# RL6678_IP_SVD register map
Vendor: Realtek
Registers are 32-bit, read-write, reset 0x0 unless marked. A register's access mark holds for its fields unless they carry their own. Offsets are from the block's base; [hi:lo] are bit positions; {n}, {i} and the like mark numbered series.

## TXPWR_CTRL
Base 0x40000000
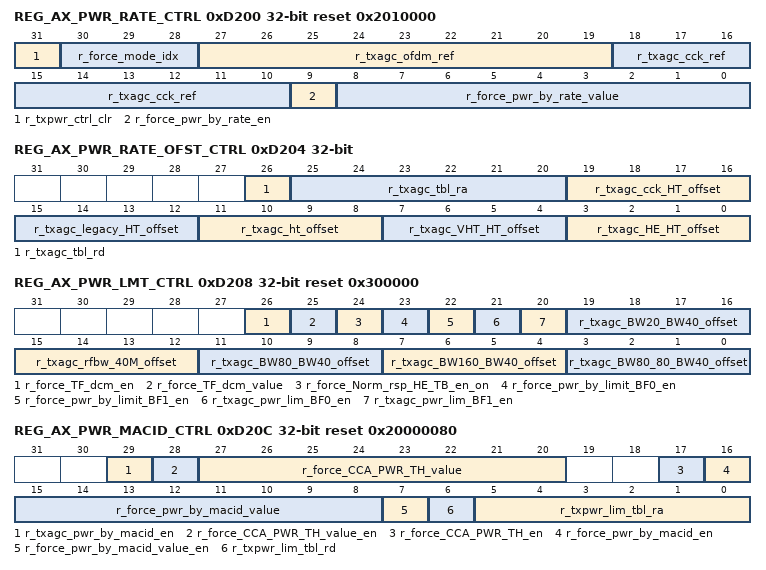
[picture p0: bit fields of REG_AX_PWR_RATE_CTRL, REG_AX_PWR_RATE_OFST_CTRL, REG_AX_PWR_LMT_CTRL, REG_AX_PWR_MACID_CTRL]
0xD200 REG_AX_PWR_RATE_CTRL reset 0x2010000
  [31] r_txpwr_ctrl_clr — (RTL_only) 1: clr txpwr, sync rst
  [30:28] r_force_mode_idx — Force txpwr_bb from specific source 0:FOCRE_NONE (normal) 1:FORCE_PWR_BY_RATE 2:FORCE_MACID 3:FORCE_PWR_LIM 4:FORCE_PWR_RU_LIM 5:FORCE_COEXIST
  [27:19] r_txagc_ofdm_ref — S(9.2) ofdm ref dbm
  [18:10] r_txagc_cck_ref — S(9.2) cck ref dbm
  [9] r_force_pwr_by_rate_en — force pwr by rate value_en
  [8:0] r_force_pwr_by_rate_value — S(9.2) force pwr by rate value (txagc_ref+pwr_by_rate_tbl)
0xD204 REG_AX_PWR_RATE_OFST_CTRL
  [26] r_txagc_tbl_rd — (RTL_only) 1:indirecr read enable
  [25:20] r_txagc_tbl_ra — (RTL_only) indirect read of addr of pwr_by_rate
  [19:16] r_txagc_cck_HT_offset — S(4.1)CCK-HT pwr offset
  [15:12] r_txagc_legacy_HT_offset — S(4.1)LEG-HT pwr offset
  [11:8] r_txagc_ht_offset — (RTL_only) S(4.1) HT-HT pwr bias = 0
  [7:4] r_txagc_VHT_HT_offset — S(4.1)VHT-HT pwr offset
  [3:0] r_txagc_HE_HT_offset — S(4.1)HE-HT pwr offset
0xD208 REG_AX_PWR_LMT_CTRL reset 0x300000
  [26] r_force_TF_dcm_en — (RTL_only) 1:Force input TF dcm = R_force_TF_dcm_value
  [25] r_force_TF_dcm_value — (RTL_only) Force input TF dcm value
  [24] r_force_Norm_rsp_HE_TB_en_on — (RTL_only) 1:Norm resp always In HE_TB
  [23] r_force_pwr_by_limit_BF0_en — (RTL_only) 1: Force pwr_lim_BF0= r_force_pwr_by_limit_bfoff_value (0xd210[17:9])
  [22] r_force_pwr_by_limit_BF1_en — (RTL_only) 1: Force pwr_lim_BF1= r_force_pwr_by_limit_bfon_value (0xd210[8:0])
  [21] r_txagc_pwr_lim_BF0_en — (RTL_only) None BF pwr limit enable
  [20] r_txagc_pwr_lim_BF1_en — (RTL_only) BF pwr limit enable
  [19:16] r_txagc_BW20_BW40_offset — S(4.1)BW20 - BW40 pwr offset
  [15:12] r_txagc_rfbw_40M_offset — (RTL_only) S(4.1)BW40 - BW40 pwr offset
  [11:8] r_txagc_BW80_BW40_offset — S(4.1)BW80 - BW40 pwr offset
  [7:4] r_txagc_BW160_BW40_offset — S(4.1)BW160 - BW40 pwr offset
  [3:0] r_txagc_BW80_80_BW40_offset — S(4.1) BW80+80 - BW40 pwr offset
0xD20C REG_AX_PWR_MACID_CTRL reset 0x20000080
  [29] r_txagc_pwr_by_macid_en — (RTL_only) 1:enable pwr_by_macid
  [28] r_force_CCA_PWR_TH_value_en — 1:Force CCA_PWR_TH value_en
  [27:20] r_force_CCA_PWR_TH_value — S(8.1)Force CCA_PWR_TH value
  [17] r_force_CCA_PWR_TH_en — (RTL_only) 1:Force output CCA_PWR_TH_en
  [16] r_force_pwr_by_macid_en — 1:Force output Pwr_by_macid_en
  [15:8] r_force_pwr_by_macid_value — S(8.1)Force Pwr_by_macid_value
  [7] r_force_pwr_by_macid_value_en — (RTL_only) 1:Force output Pwr_by_macid_value
  [6] r_txpwr_lim_tbl_rd — (RTL_only) 1: pwr lim tbl indirect read en
  [5:0] r_txpwr_lim_tbl_ra — (RTL_only) pwr lim tbl indirect read addr
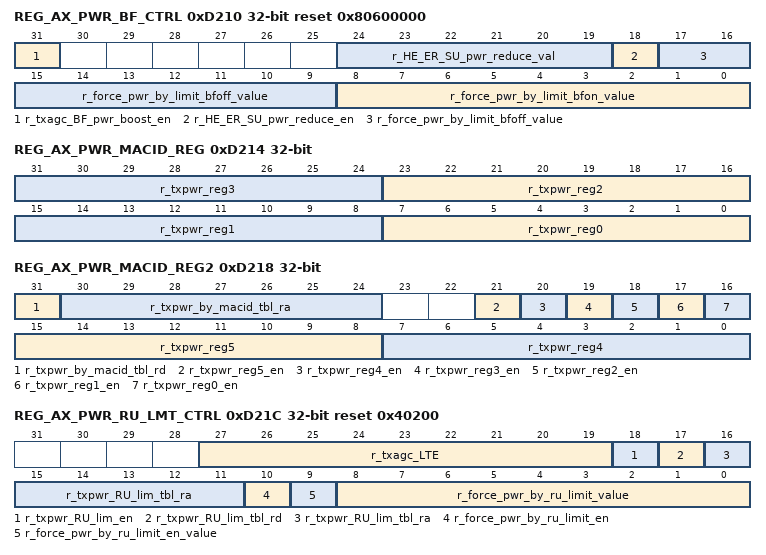
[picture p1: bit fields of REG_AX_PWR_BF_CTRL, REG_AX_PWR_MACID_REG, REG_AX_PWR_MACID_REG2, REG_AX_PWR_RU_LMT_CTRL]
0xD210 REG_AX_PWR_BF_CTRL reset 0x80600000
  [31] r_txagc_BF_pwr_boost_en — 1:TxBF will cal pwr boost to BB 0:TxBF pwr_boost =0 & Pwr_lim use BF1_pwr_lim
  [24:19] r_HE_ER_SU_pwr_reduce_val — (RTL_only) S(6.2) 3dB=0xC
  [18] r_HE_ER_SU_pwr_reduce_en — 1:HE_ER_SU pwr lim output will minus 3dB
  [17:9] r_force_pwr_by_limit_bfoff_value — S(9.2) r_force_pwr_by_limit_BF0_en=1 is valid
  [8:0] r_force_pwr_by_limit_bfon_value — S(9.2) r_force_pwr_by_limit_BF1_en=1 is valid
0xD214 REG_AX_PWR_MACID_REG
  [8n+7:8n] r_txpwr_reg{n} (n=0..3) — S(8.1)pwr by macid when Pwr_mode={n+2} from MAC
0xD218 REG_AX_PWR_MACID_REG2
  [31] r_txpwr_by_macid_tbl_rd — (RTL_only) 1:Pwr_by_macid indirect read
  [30:24] r_txpwr_by_macid_tbl_ra — (RTL_only) Pwr_by_macid indirect read addr
  [21] r_txpwr_reg5_en — pwr by macid en when Pwr_mode=7 from MAC
  [20] r_txpwr_reg4_en — pwr by macid en when Pwr_mode=6 from MAC
  [19] r_txpwr_reg3_en — pwr by macid en when Pwr_mode=5 from MAC
  [18] r_txpwr_reg2_en — pwr by macid en when pwr_mode=4 from MAC
  [17] r_txpwr_reg1_en — pwr by macid en when Pwr_mode=3 from MAC
  [16] r_txpwr_reg0_en — pwr by macid en when Pwr_mode=2 from MAC
  [15:8] r_txpwr_reg5 — S(8.1)pwr by macid when Pwr_mode=7 from MAC
  [7:0] r_txpwr_reg4 — S(8.1)pwr by macid when Pwr_mode=6 from MAC
0xD21C REG_AX_PWR_RU_LMT_CTRL reset 0x40200
  [27:19] r_txagc_LTE — S(9.2) Coexist LTE pwr dbm
  [18] r_txpwr_RU_lim_en — (RTL_only) 1:Ru lim indirect read
  [17] r_txpwr_RU_lim_tbl_rd — (RTL_only) 1:Ru lim indirect read
  [16:11] r_txpwr_RU_lim_tbl_ra — (RTL_only) Ru lim indirect read addr
  [10] r_force_pwr_by_ru_limit_en — 1: RU_lim = r_force_pwr_by_ru_limit_value
  [9] r_force_pwr_by_ru_limit_en_value — (ru lim val is valid in HE_TB)
  [8:0] r_force_pwr_by_ru_limit_value — Force RU lim_val enable
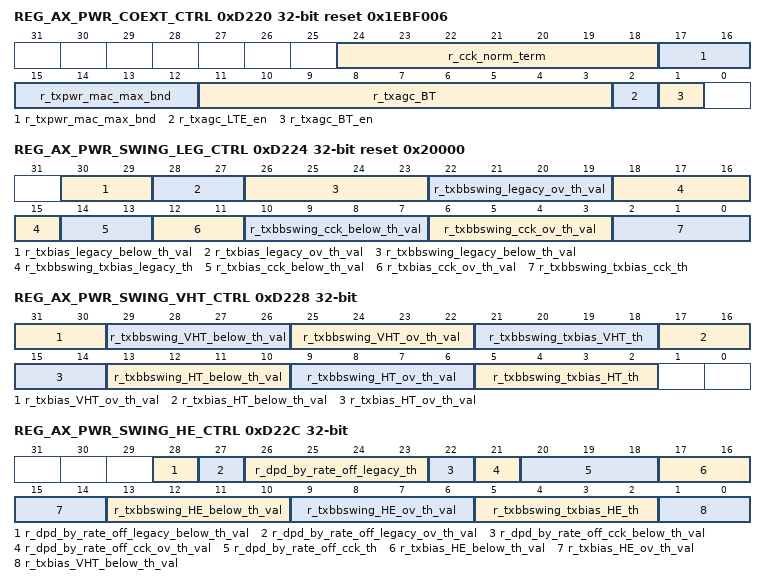
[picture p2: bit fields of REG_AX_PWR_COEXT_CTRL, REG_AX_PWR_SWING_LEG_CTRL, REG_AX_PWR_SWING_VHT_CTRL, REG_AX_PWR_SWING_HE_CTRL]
0xD220 REG_AX_PWR_COEXT_CTRL reset 0x1EBF006
  [24:18] r_cck_norm_term — (RTL_only) u(6.4) Map txpwr_bb to txpwr_mac 0x7A=20log(20/11)=2.625
  [17:12] r_txpwr_mac_max_bnd — (RTL_only) u(6.0) txpwr mac max bnd dB
  [11:3] r_txagc_BT — S(9.2) Coexist BT pwr dbm
  [2] r_txagc_LTE_en — Coexist LTE_en
  [1] r_txagc_BT_en — Coexist BT_en
0xD224 REG_AX_PWR_SWING_LEG_CTRL reset 0x20000
  [30:29] r_txbias_legacy_below_th_val — Bbswing , txbias mcs below th sel this
  [28:27] r_txbias_legacy_ov_th_val — Bbswing ,txbias mcs ov th sel this
  [26:23] r_txbbswing_legacy_below_th_val — Bbswing ,txbias mcs below th sel this
  [22:19] r_txbbswing_legacy_ov_th_val — Bbswing ,txbias mcs ov th sel this
  [18:15] r_txbbswing_txbias_legacy_th — 0~4 Bbswing txbias mcs th
  [14:13] r_txbias_cck_below_th_val — Bbswing ,txbias mcs below th sel this
  [12:11] r_txbias_cck_ov_th_val — Bbswing ,txbias mcs ov th sel this
  [10:7] r_txbbswing_cck_below_th_val — Bbswing ,txbias mcs below th sel this
  [6:3] r_txbbswing_cck_ov_th_val — Bbswing ,txbias mcs ov th sel this
  [2:0] r_txbbswing_txbias_cck_th — 0~4 Bbswing txbias mcs th
0xD228 REG_AX_PWR_SWING_VHT_CTRL
  [31:30] r_txbias_VHT_ov_th_val — Bbswing ,txbias mcs ov th sel this
  [29:26] r_txbbswing_VHT_below_th_val — Bbswing ,txbias mcs below th sel this
  [25:22] r_txbbswing_VHT_ov_th_val — Bbswing ,txbias mcs ov th sel this
  [21:18] r_txbbswing_txbias_VHT_th — 0~12 Bbswing txbias mcs th
  [17:16] r_txbias_HT_below_th_val — Bbswing ,txbias mcs below th sel this
  [15:14] r_txbias_HT_ov_th_val — Bbswing ,txbias mcs ov th sel this
  [13:10] r_txbbswing_HT_below_th_val — Bbswing ,txbias mcs below th sel this
  [9:6] r_txbbswing_HT_ov_th_val — Bbswing ,txbias mcs ov th sel this
  [5:2] r_txbbswing_txbias_HT_th — 0~8 Bbswing txbias mcs th
0xD22C REG_AX_PWR_SWING_HE_CTRL
  [28] r_dpd_by_rate_off_legacy_below_th_val — Bbswing ,txbias mcs below th sel this
  [27] r_dpd_by_rate_off_legacy_ov_th_val — Bbswing ,txbias mcs ov th sel this
  [26:23] r_dpd_by_rate_off_legacy_th — 4~8 Bbswing txbias mcs th
  [22] r_dpd_by_rate_off_cck_below_th_val — Bbswing ,txbias mcs below th sel this
  [21] r_dpd_by_rate_off_cck_ov_th_val — Bbswing ,txbias mcs ov th sel this
  [20:18] r_dpd_by_rate_off_cck_th — 0~4 Bbswing txbias mcs th
  [17:16] r_txbias_HE_below_th_val — Bbswing ,txbias mcs below th sel this
  [15:14] r_txbias_HE_ov_th_val — Bbswing ,txbias mcs ov th sel this
  [13:10] r_txbbswing_HE_below_th_val — Bbswing ,txbias mcs below th sel this
  [9:6] r_txbbswing_HE_ov_th_val — Bbswing ,txbias mcs ov th sel this
  [5:2] r_txbbswing_txbias_HE_th — 0~12 Bbswing txbias mcs th
  [1:0] r_txbias_VHT_below_th_val — Bbswing ,txbias mcs ov th sel this
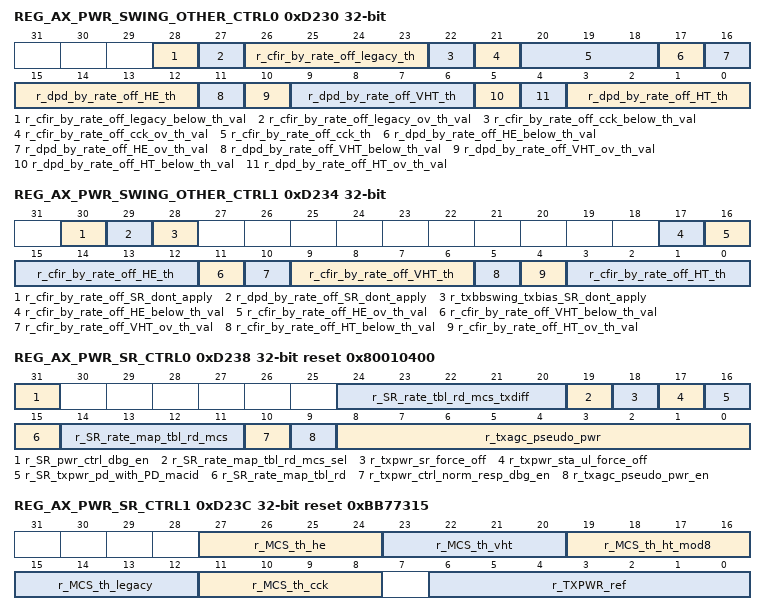
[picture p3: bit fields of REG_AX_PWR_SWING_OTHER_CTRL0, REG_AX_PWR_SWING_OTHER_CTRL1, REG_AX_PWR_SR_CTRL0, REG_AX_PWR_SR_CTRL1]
0xD230 REG_AX_PWR_SWING_OTHER_CTRL0
  [28] r_cfir_by_rate_off_legacy_below_th_val — dpd by rate off mcs below th sel this
  [27] r_cfir_by_rate_off_legacy_ov_th_val — dpd by rate off mcs ov th sel this
  [26:23] r_cfir_by_rate_off_legacy_th — 4~8 dpd by rate off mcs ov th
  [22] r_cfir_by_rate_off_cck_below_th_val — dpd by rate off mcs below th sel this
  [21] r_cfir_by_rate_off_cck_ov_th_val — dpd by rate off mcs ov th sel this
  [20:18] r_cfir_by_rate_off_cck_th — 0~4 dpd by rate off mcs th
  [17] r_dpd_by_rate_off_HE_below_th_val — cfir by rate_off mcs below th sel this
  [16] r_dpd_by_rate_off_HE_ov_th_val — cfir by rate_off mcs ov th sel this
  [15:12] r_dpd_by_rate_off_HE_th — 0~12 cfir by rate_off mcs th
  [11] r_dpd_by_rate_off_VHT_below_th_val — cfir by rate_off mcs below th sel this
  [10] r_dpd_by_rate_off_VHT_ov_th_val — cfir by rate_off mcs ov th sel this
  [9:6] r_dpd_by_rate_off_VHT_th — 0~12 cfir by rate_off mcs th
  [5] r_dpd_by_rate_off_HT_below_th_val — cfir by rate_off mcs below th sel this
  [4] r_dpd_by_rate_off_HT_ov_th_val — cfir by rate_off mcs ov th sel this
  [3:0] r_dpd_by_rate_off_HT_th — 0~8 cfir by rate_off mcs th
0xD234 REG_AX_PWR_SWING_OTHER_CTRL1
  [30] r_cfir_by_rate_off_SR_dont_apply — (RTL_only) 1:Disable at SR
  [29] r_dpd_by_rate_off_SR_dont_apply — (RTL_only) 1:Disable at SR
  [28] r_txbbswing_txbias_SR_dont_apply — (RTL_only) 1:Disable at SR
  [17] r_cfir_by_rate_off_HE_below_th_val — dpd by rate off mcs below th sel this
  [16] r_cfir_by_rate_off_HE_ov_th_val — dpd by rate off mcs ov th sel this
  [15:12] r_cfir_by_rate_off_HE_th — 0~12 dpd by rate off mcs ov th
  [11] r_cfir_by_rate_off_VHT_below_th_val — dpd by rate off mcs below th sel this
  [10] r_cfir_by_rate_off_VHT_ov_th_val — dpd by rate off mcs ov th sel this
  [9:6] r_cfir_by_rate_off_VHT_th — 0~12 dpd by rate off mcs ov th
  [5] r_cfir_by_rate_off_HT_below_th_val — dpd by rate off mcs below th sel this
  [4] r_cfir_by_rate_off_HT_ov_th_val — dpd by rate off mcs ov th sel this
  [3:0] r_cfir_by_rate_off_HT_th — 0~8 dpd by rate off mcs ov th
0xD238 REG_AX_PWR_SR_CTRL0 reset 0x80010400
  [31] r_SR_pwr_ctrl_dbg_en — (RTL_only) 0:saving pwr
  [24:20] r_SR_rate_tbl_rd_mcs_txdiff — (RTL_only) Rd MEM idx 0~47
  [19] r_SR_rate_map_tbl_rd_mcs_sel — (RTL_only) 1:cckle 0~11 0:ht/vht/he 0~11
  [18] r_txpwr_sr_force_off — (RTL_only) 1:force sr mode off
  [17] r_txpwr_sta_ul_force_off — (RTL_only) 1:force sta mode off
  [16] r_SR_txpwr_pd_with_PD_macid — (RTL_only) 1:txpwr_PD from internal buffer 0: from MAC
  [15] r_SR_rate_map_tbl_rd — (RTL_only) 1:indirect read of addr
  [14:11] r_SR_rate_map_tbl_rd_mcs — (RTL_only) indirect read of addr
  [10] r_txpwr_ctrl_norm_resp_dbg_en — (RTL_only) 0:dbg clk off for saving pwr
  [9] r_txagc_pseudo_pwr_en — (RTL_only) 1: force on norm resp out txpwr_bb
  [8:0] r_txagc_pseudo_pwr — (RTL_only) S(9.2) force norm resp out txpwr_bb
0xD23C REG_AX_PWR_SR_CTRL1 reset 0xBB77315
  [27:24] r_MCS_th_he — SR MCS0~MCS11
  [23:20] r_MCS_th_vht — SR MCS0~MCS11
  [19:16] r_MCS_th_ht_mod8 — SR MCS0~MCS7
  [15:12] r_MCS_th_legacy — SR 4~11
  [11:8] r_MCS_th_cck — SR 0~3
  [6:0] r_TXPWR_ref — SR txpwr ref(txpwr_mcs diff)
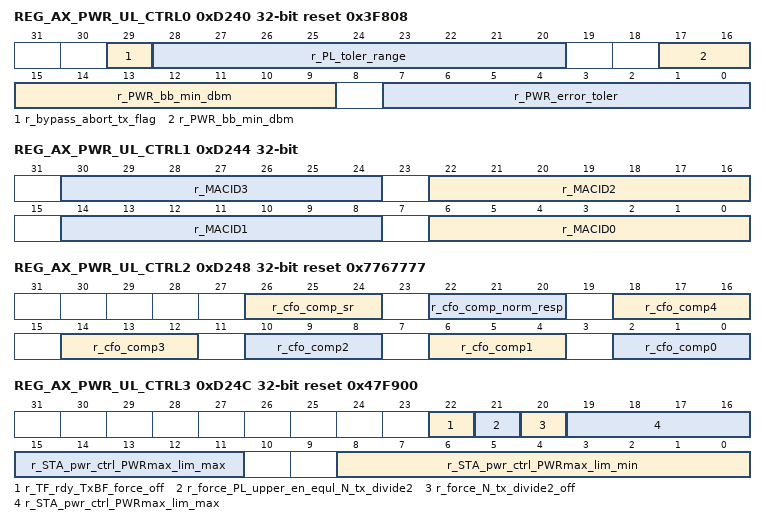
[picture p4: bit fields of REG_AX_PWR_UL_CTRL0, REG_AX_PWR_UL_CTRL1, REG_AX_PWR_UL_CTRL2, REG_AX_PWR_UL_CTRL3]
0xD240 REG_AX_PWR_UL_CTRL0 reset 0x3F808
  [29] r_bypass_abort_tx_flag — 1: force off abort_tx flag STA_UL
  [28:20] r_PL_toler_range — U(9.2) STA_UL
  [17:9] r_PWR_bb_min_dbm — S(9.2) STA_UL
  [7:0] r_PWR_error_toler — S(9.2) STA_UL
0xD244 REG_AX_PWR_UL_CTRL1
  [8n+6:8n] r_MACID{n} (n=0..3) — STA_UL
0xD248 REG_AX_PWR_UL_CTRL2 reset 0x7767777
  [26:24] r_cfo_comp_sr — (RTL_only) STA_UL no need to set
  [22:20] r_cfo_comp_norm_resp — (RTL_only) STA_UL no need to set
  [18:16] r_cfo_comp4 — (RTL_only) STA_UL Default 6 no need to set
  [4n+2:4n] r_cfo_comp{n} (n=0..3) — STA_UL
0xD24C REG_AX_PWR_UL_CTRL3 reset 0x47F900
  [22] r_TF_rdy_TxBF_force_off — (RTL_only) Jorden Sta_UL doesnt have TxBF
  [21] r_force_PL_upper_en_equl_N_tx_divide2 — (RTL_only) 1:PL_upper_en = is N_tx/2
  [20] r_force_N_tx_divide2_off — (RTL_only) 1:force off N_tx/2
  [19:11] r_STA_pwr_ctrl_PWRmax_lim_max — (RTL_only) S(9.2) Limit pwr from norm resp
  [8:0] r_STA_pwr_ctrl_PWRmax_lim_min — (RTL_only) S(9.2) Limit pwr from norm resp
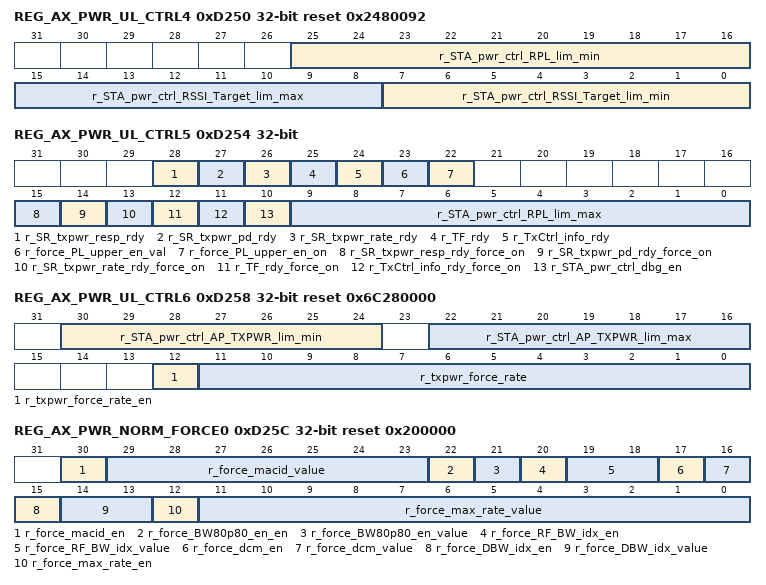
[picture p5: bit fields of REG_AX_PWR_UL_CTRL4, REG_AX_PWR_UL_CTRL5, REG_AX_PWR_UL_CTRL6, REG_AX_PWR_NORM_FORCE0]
0xD250 REG_AX_PWR_UL_CTRL4 reset 0x2480092
  [25:16] r_STA_pwr_ctrl_RPL_lim_min — (RTL_only) S(10.2) Min=-110 (-440) Limit RPL
  [15:8] r_STA_pwr_ctrl_RSSI_Target_lim_max — (RTL_only) S(8.0) Max:0 Limit RSSI_Target
  [7:0] r_STA_pwr_ctrl_RSSI_Target_lim_min — (RTL_only) S(8.0) Min=-110 Limit RSSI_Target
0xD254 REG_AX_PWR_UL_CTRL5
  [28] r_SR_txpwr_resp_rdy — (RTL_only) 1: trig when r_SR_txpwr_resp_rdy_force_on
  [27] r_SR_txpwr_pd_rdy — (RTL_only) 1: trig when r_SR_txpwr_pd_rdy_force_on
  [26] r_SR_txpwr_rate_rdy — (RTL_only) 1: trig when r_SR_txpwr_rate_rdy_force_on
  [25] r_TF_rdy — (RTL_only) 1: trig when r_TF_rdy_force_on
  [24] r_TxCtrl_info_rdy — (RTL_only) 1: trig when r_TxCtrl_info_rdy_force_on
  [23] r_force_PL_upper_en_val
  [22] r_force_PL_upper_en_on — (RTL_only) 1 : PL_upper_en = r_force_PL_upper_en_val
  [15] r_SR_txpwr_resp_rdy_force_on — (RTL_only) 1:force off SR resp trigger
  [14] r_SR_txpwr_pd_rdy_force_on — (RTL_only) 1:force off SR MCS flow trigger
  [13] r_SR_txpwr_rate_rdy_force_on — (RTL_only) 1:force off SR PD flow trigger
  [12] r_TF_rdy_force_on — (RTL_only) 1:force off TF trigger
  [11] r_TxCtrl_info_rdy_force_on — (RTL_only) 1:force off norm resp trigger
  [10] r_STA_pwr_ctrl_dbg_en — (RTL_only) 0: pwr saving
  [9:0] r_STA_pwr_ctrl_RPL_lim_max — (RTL_only) S(10.2) Max:0 Limit RPL
0xD258 REG_AX_PWR_UL_CTRL6 reset 0x6C280000
  [30:24] r_STA_pwr_ctrl_AP_TXPWR_lim_min — (RTL_only) S(7.0 ) MIN=-20 Limit AP TXPWR
  [22:16] r_STA_pwr_ctrl_AP_TXPWR_lim_max — (RTL_only) S(7.0 ) MAX=+40 Limit AP TXPWR
  [12] r_txpwr_force_rate_en — (RTL_only) No use
  [11:0] r_txpwr_force_rate — (RTL_only) No use
0xD25C REG_AX_PWR_NORM_FORCE0 reset 0x200000
  [30] r_force_macid_en — (RTL_only) Force input from MAC
  [29:23] r_force_macid_value — (RTL_only) Force input from MAC
  [22] r_force_BW80p80_en_en — (RTL_only) Force input from MAC
  [21] r_force_BW80p80_en_value — (RTL_only) Force input from MAC
  [20] r_force_RF_BW_idx_en — (RTL_only) Force input from MAC
  [19:18] r_force_RF_BW_idx_value — (RTL_only) Force input from MAC
  [17] r_force_dcm_en — (RTL_only) Force input from MAC
  [16] r_force_dcm_value — (RTL_only) Force input from MAC
  [15] r_force_DBW_idx_en — (RTL_only) Force input from MAC
  [14:13] r_force_DBW_idx_value — (RTL_only) Force input from MAC
  [12] r_force_max_rate_en — (RTL_only) Force input from MAC
  [11:0] r_force_max_rate_value — (RTL_only) Force input from MAC
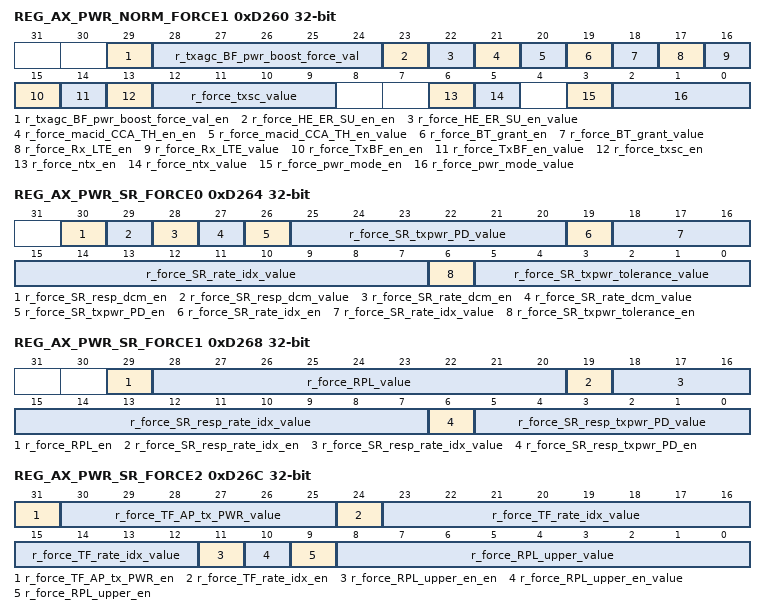
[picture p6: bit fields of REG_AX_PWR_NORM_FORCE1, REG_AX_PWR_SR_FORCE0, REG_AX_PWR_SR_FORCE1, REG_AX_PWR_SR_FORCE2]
0xD260 REG_AX_PWR_NORM_FORCE1
  [29] r_txagc_BF_pwr_boost_force_val_en — (RTL_only) Force input from MAC en
  [28:24] r_txagc_BF_pwr_boost_force_val — (RTL_only) Force input from MAC
  [23] r_force_HE_ER_SU_en_en — (RTL_only) Force input from MAC en
  [22] r_force_HE_ER_SU_en_value — (RTL_only) Force input from MAC
  [21] r_force_macid_CCA_TH_en_en — (RTL_only) Force input from MAC en
  [20] r_force_macid_CCA_TH_en_value — (RTL_only) Force input from MAC
  [19] r_force_BT_grant_en — (RTL_only) Force input from MAC en
  [18] r_force_BT_grant_value — (RTL_only) Force input from MAC
  [17] r_force_Rx_LTE_en — (RTL_only) Force input from MAC en
  [16] r_force_Rx_LTE_value — (RTL_only) Force input from MAC
  [15] r_force_TxBF_en_en — (RTL_only) Force input from MAC en
  [14] r_force_TxBF_en_value — (RTL_only) Force input from MAC
  [13] r_force_txsc_en — (RTL_only) Force input from MAC en
  [12:9] r_force_txsc_value — (RTL_only) Force input from MAC
  [6] r_force_ntx_en — (RTL_only) Force input from MAC en
  [5] r_force_ntx_value — (RTL_only) Force input from MAC
  [3] r_force_pwr_mode_en — (RTL_only) Force input from MAC en
  [2:0] r_force_pwr_mode_value — (RTL_only) Force input from MAC
0xD264 REG_AX_PWR_SR_FORCE0
  [30] r_force_SR_resp_dcm_en — (RTL_only) Force input from MAC en
  [29] r_force_SR_resp_dcm_value — (RTL_only) Force input from MAC
  [28] r_force_SR_rate_dcm_en — (RTL_only) Force input from MAC en
  [27] r_force_SR_rate_dcm_value — (RTL_only) Force input from MAC
  [26] r_force_SR_txpwr_PD_en — (RTL_only) Force input from MAC en
  [25:20] r_force_SR_txpwr_PD_value — (RTL_only) Force input from MAC
  [19] r_force_SR_rate_idx_en — (RTL_only) Force input from MAC en
  [18:7] r_force_SR_rate_idx_value — (RTL_only) Force input from MAC
  [6] r_force_SR_txpwr_tolerance_en — (RTL_only) Force input from MAC en
  [5:0] r_force_SR_txpwr_tolerance_value — (RTL_only) Force input from MAC
0xD268 REG_AX_PWR_SR_FORCE1
  [29] r_force_RPL_en — (RTL_only) Force input from MAC en
  [28:20] r_force_RPL_value — (RTL_only) Force input from MAC
  [19] r_force_SR_resp_rate_idx_en — (RTL_only) Force input from MAC en
  [18:7] r_force_SR_resp_rate_idx_value — (RTL_only) Force input from MAC
  [6] r_force_SR_resp_txpwr_PD_en — (RTL_only) Force input from MAC en
  [5:0] r_force_SR_resp_txpwr_PD_value — (RTL_only) Force input from MAC
0xD26C REG_AX_PWR_SR_FORCE2
  [31] r_force_TF_AP_tx_PWR_en — (RTL_only) Force input from MAC en
  [30:25] r_force_TF_AP_tx_PWR_value — (RTL_only) Force input from MAC
  [24] r_force_TF_rate_idx_en — (RTL_only) Force input from MAC en
  [23:12] r_force_TF_rate_idx_value — (RTL_only) Force input from MAC
  [11] r_force_RPL_upper_en_en — (RTL_only) Force input from MAC en
  [10] r_force_RPL_upper_en_value — (RTL_only) Force input from MAC
  [9] r_force_RPL_upper_en — (RTL_only) Force input from MAC en
  [8:0] r_force_RPL_upper_value — (RTL_only) Force input from MAC
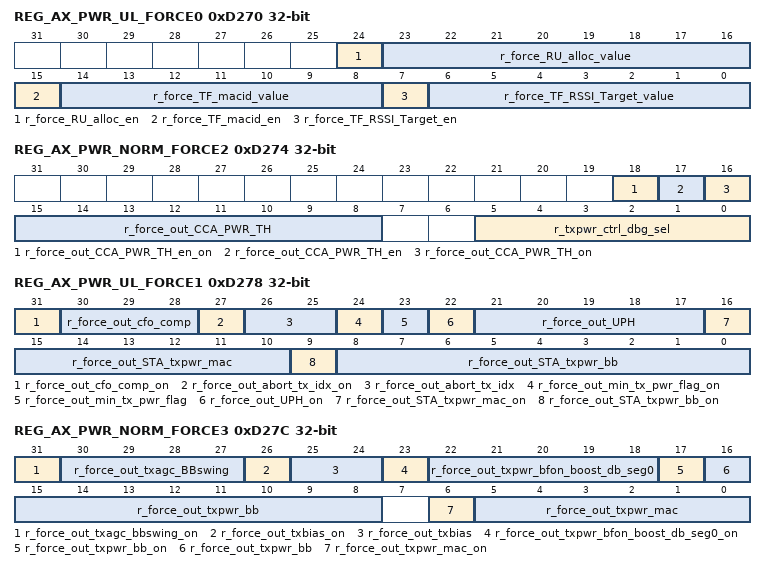
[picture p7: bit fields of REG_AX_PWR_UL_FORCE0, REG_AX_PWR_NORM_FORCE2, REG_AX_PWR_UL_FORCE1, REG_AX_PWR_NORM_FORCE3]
0xD270 REG_AX_PWR_UL_FORCE0
  [24] r_force_RU_alloc_en — (RTL_only) Force input from MAC en
  [23:16] r_force_RU_alloc_value — (RTL_only) Force input from MAC
  [15] r_force_TF_macid_en — (RTL_only) Force input from MAC en
  [14:8] r_force_TF_macid_value — (RTL_only) Force input from MAC
  [7] r_force_TF_RSSI_Target_en — (RTL_only) Force input from MAC en
  [6:0] r_force_TF_RSSI_Target_value — (RTL_only) Force input from MAC
0xD274 REG_AX_PWR_NORM_FORCE2
  [18] r_force_out_CCA_PWR_TH_en_on — (RTL_only) Force output to MAC en
  [17] r_force_out_CCA_PWR_TH_en — (RTL_only) Force output to MAC
  [16] r_force_out_CCA_PWR_TH_on — (RTL_only) Force output to MAC en
  [15:8] r_force_out_CCA_PWR_TH — (RTL_only) Force output to MAC
  [5:0] r_txpwr_ctrl_dbg_sel — (RTL_only) dbg port address
0xD278 REG_AX_PWR_UL_FORCE1
  [31] r_force_out_cfo_comp_on — (RTL_only) Force output to MAC en
  [30:28] r_force_out_cfo_comp — (RTL_only) Force output to MAC
  [27] r_force_out_abort_tx_idx_on — (RTL_only) Force output to MAC en
  [26:25] r_force_out_abort_tx_idx — (RTL_only) Force output to MAC
  [24] r_force_out_min_tx_pwr_flag_on — (RTL_only) Force output to MAC en
  [23] r_force_out_min_tx_pwr_flag — (RTL_only) Force output to MAC
  [22] r_force_out_UPH_on — (RTL_only) Force output to MAC en
  [21:17] r_force_out_UPH — (RTL_only) Force output to MAC
  [16] r_force_out_STA_txpwr_mac_on — (RTL_only) Force output to MAC en
  [15:10] r_force_out_STA_txpwr_mac — (RTL_only) Force output to MAC
  [9] r_force_out_STA_txpwr_bb_on — (RTL_only) Force output to MAC en
  [8:0] r_force_out_STA_txpwr_bb — (RTL_only) Force output to MAC
0xD27C REG_AX_PWR_NORM_FORCE3
  [31] r_force_out_txagc_bbswing_on — (RTL_only) Force output to MAC en
  [30:27] r_force_out_txagc_BBswing — (RTL_only) Force output to MAC
  [26] r_force_out_txbias_on — (RTL_only) Force output to MAC en
  [25:24] r_force_out_txbias — (RTL_only) Force output to MAC
  [23] r_force_out_txpwr_bfon_boost_db_seg0_on — (RTL_only) Force output to MAC en
  [22:18] r_force_out_txpwr_bfon_boost_db_seg0 — (RTL_only) Force output to MAC
  [17] r_force_out_txpwr_bb_on — (RTL_only) Force output to MAC en
  [16:8] r_force_out_txpwr_bb — (RTL_only) Force output to MAC
  [6] r_force_out_txpwr_mac_on — (RTL_only) Force output to MAC en
  [5:0] r_force_out_txpwr_mac — (RTL_only) Force output to MAC
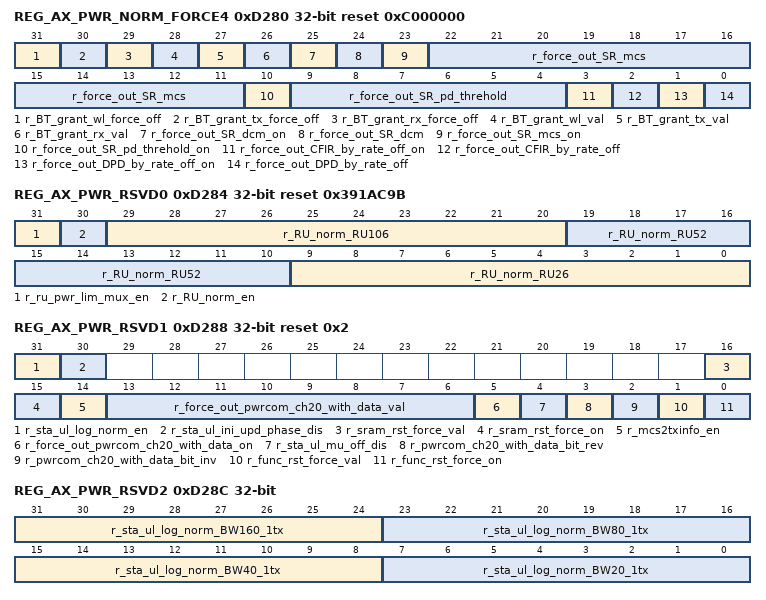
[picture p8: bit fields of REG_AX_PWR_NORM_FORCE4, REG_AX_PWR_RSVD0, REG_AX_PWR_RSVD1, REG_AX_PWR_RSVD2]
0xD280 REG_AX_PWR_NORM_FORCE4 reset 0xC000000
  [31] r_BT_grant_wl_force_off — (RTL_only) Force off grant_wl
  [30] r_BT_grant_tx_force_off — (RTL_only) Force off grant_tx
  [29] r_BT_grant_rx_force_off — (RTL_only) Force off grant_rx
  [28] r_BT_grant_wl_val — (RTL_only) grant_wl flag=0 means coexist act
  [27] r_BT_grant_tx_val — (RTL_only) grant_rx flag=1 means coexist act
  [26] r_BT_grant_rx_val — (RTL_only) grant_rx flag=1 means coexist act
  [25] r_force_out_SR_dcm_on — (RTL_only) Force output to MAC en
  [24] r_force_out_SR_dcm — (RTL_only) Force output to MAC
  [23] r_force_out_SR_mcs_on — (RTL_only) Force output to MAC en
  [22:11] r_force_out_SR_mcs — (RTL_only) Force output to MAC
  [10] r_force_out_SR_pd_threhold_on — (RTL_only) Force output to MAC en
  [9:4] r_force_out_SR_pd_threhold — (RTL_only) Force output to MAC
  [3] r_force_out_CFIR_by_rate_off_on — (RTL_only) Force output to MAC en
  [2] r_force_out_CFIR_by_rate_off — (RTL_only) Force output to MAC
  [1] r_force_out_DPD_by_rate_off_on — (RTL_only) Force output to MAC en
  [0] r_force_out_DPD_by_rate_off — (RTL_only) Force output to MAC
0xD284 REG_AX_PWR_RSVD0 reset 0x391AC9B
  [31] r_ru_pwr_lim_mux_en — 1:by_rate->macid_lim->RU_lim 0:by_rate->macid->BF0_pwr_lim->RU_lim
  [30] r_RU_norm_en — (RTL_only) RU_norm_enable (RTL_ONLY TEST )
  [29:20] r_RU_norm_RU106 — (RTL_only) S(10.4) RU_lim tbl -RU norm,0x39=3.5625dB
  [19:10] r_RU_norm_RU52 — (RTL_only) S(10.4) RU_lim tbl -RU norm,0x6b=6.6875dB
  [9:0] r_RU_norm_RU26 — (RTL_only) S(10.4) RU_lim tbl -RU norm ,0x9b=9.6875dB
0xD288 REG_AX_PWR_RSVD1 reset 0x2
  [31] r_sta_ul_log_norm_en — 1:sta ul txpwr log norm en 0:log norm=10log(ntx)-10log(dbw)
  [30] r_sta_ul_ini_upd_phase_dis — 1:tst non eco bug
  [16] r_sram_rst_force_val — rst sram by cr
  [15] r_sram_rst_force_on — 1:rst sram by cr
  [14] r_mcs2txinfo_en — 1:txinfo_bbswing=MCS
  [13:6] r_force_out_pwrcom_ch20_with_data_val — 1:force out off
  [5] r_force_out_pwrcom_ch20_with_data_on — 1:force out on
  [4] r_sta_ul_mu_off_dis — 1:MU do sta_ul
  [3] r_pwrcom_ch20_with_data_bit_rev — bit rev,txpwr_lim
  [2] r_pwrcom_ch20_with_data_bit_inv — bit inv,txpwr_lim
  [1] r_func_rst_force_val — func rst from txpwr_ctrl _CR
  [0] r_func_rst_force_on — Don't obey func rst from MAC
0xD28C REG_AX_PWR_RSVD2
  [31:24] r_sta_ul_log_norm_BW160_1tx — s(8,2) sta ul txpwr log norm
  [23:16] r_sta_ul_log_norm_BW80_1tx — s(8,2) sta ul txpwr log norm
  [15:8] r_sta_ul_log_norm_BW40_1tx — s(8,2) sta ul txpwr log norm
  [7:0] r_sta_ul_log_norm_BW20_1tx — s(8,2) sta ul txpwr log norm
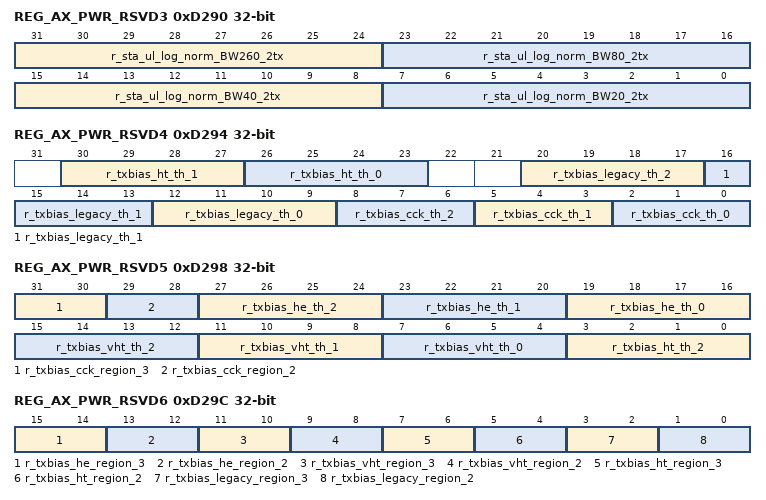
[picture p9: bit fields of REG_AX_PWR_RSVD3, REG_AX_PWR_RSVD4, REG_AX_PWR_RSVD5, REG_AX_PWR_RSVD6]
0xD290 REG_AX_PWR_RSVD3
  [31:24] r_sta_ul_log_norm_BW260_2tx — s(8,2) sta ul txpwr log norm
  [23:16] r_sta_ul_log_norm_BW80_2tx — s(8,2) sta ul txpwr log norm
  [15:8] r_sta_ul_log_norm_BW40_2tx — s(8,2) sta ul txpwr log norm
  [7:0] r_sta_ul_log_norm_BW20_2tx — s(8,2) sta ul txpwr log norm
0xD294 REG_AX_PWR_RSVD4
  [30:27] r_txbias_ht_th_1 — txbias region
  [26:23] r_txbias_ht_th_0 — txbias region
  [20:17] r_txbias_legacy_th_2 — txbias region
  [16:13] r_txbias_legacy_th_1 — txbias region
  [12:9] r_txbias_legacy_th_0 — txbias region
  [8:6] r_txbias_cck_th_2 — txbias region
  [5:3] r_txbias_cck_th_1 — txbias region
  [2:0] r_txbias_cck_th_0 — txbias region
0xD298 REG_AX_PWR_RSVD5
  [31:30] r_txbias_cck_region_3 — txbias region
  [29:28] r_txbias_cck_region_2 — txbias region
  [27:24] r_txbias_he_th_2 — txbias region
  [23:20] r_txbias_he_th_1 — txbias region
  [19:16] r_txbias_he_th_0 — txbias region
  [15:12] r_txbias_vht_th_2 — txbias region
  [11:8] r_txbias_vht_th_1 — txbias region
  [7:4] r_txbias_vht_th_0 — txbias region
  [3:0] r_txbias_ht_th_2 — txbias region
0xD29C REG_AX_PWR_RSVD6
  [15:14] r_txbias_he_region_3 — txbias region
  [13:12] r_txbias_he_region_2 — txbias region
  [11:10] r_txbias_vht_region_3 — txbias region
  [9:8] r_txbias_vht_region_2 — txbias region
  [7:6] r_txbias_ht_region_3 — txbias region
  [5:4] r_txbias_ht_region_2 — txbias region
  [3:2] r_txbias_legacy_region_3 — txbias region
  [1:0] r_txbias_legacy_region_2 — txbias region
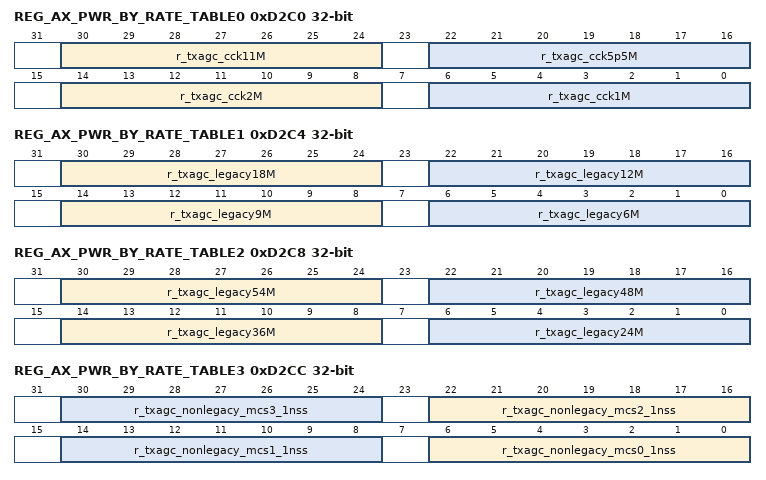
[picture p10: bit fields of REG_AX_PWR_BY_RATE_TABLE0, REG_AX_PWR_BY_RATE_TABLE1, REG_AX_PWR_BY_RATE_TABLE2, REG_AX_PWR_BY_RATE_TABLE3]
0xD2C0 REG_AX_PWR_BY_RATE_TABLE0
  [30:24] r_txagc_cck11M — s(7.1)
  [22:16] r_txagc_cck5p5M — s(7.1)
  [14:8] r_txagc_cck2M — s(7.1)
  [6:0] r_txagc_cck1M — s(7.1)
0xD2C4 REG_AX_PWR_BY_RATE_TABLE1
  [30:24] r_txagc_legacy18M — s(7.1)
  [22:16] r_txagc_legacy12M — s(7.1)
  [14:8] r_txagc_legacy9M — s(7.1)
  [6:0] r_txagc_legacy6M — s(7.1)
0xD2C8 REG_AX_PWR_BY_RATE_TABLE2
  [30:24] r_txagc_legacy54M — s(7.1)
  [22:16] r_txagc_legacy48M — s(7.1)
  [14:8] r_txagc_legacy36M — s(7.1)
  [6:0] r_txagc_legacy24M — s(7.1)
0xD2CC REG_AX_PWR_BY_RATE_TABLE3
  [8n+6:8n] r_txagc_nonlegacy_mcs{n}_1nss (n=0..3) — s(7.1)
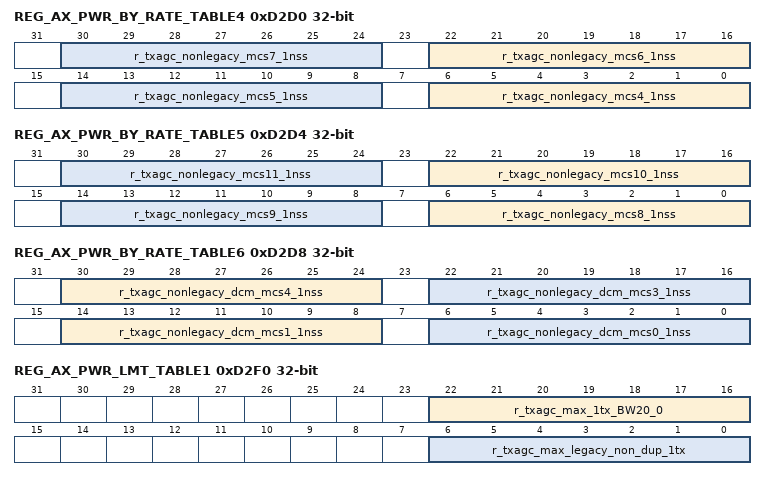
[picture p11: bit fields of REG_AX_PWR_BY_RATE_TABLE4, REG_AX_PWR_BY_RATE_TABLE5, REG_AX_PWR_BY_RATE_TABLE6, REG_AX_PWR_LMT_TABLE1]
0xD2D0 REG_AX_PWR_BY_RATE_TABLE4
  [8n-26:8n-32] r_txagc_nonlegacy_mcs{n}_1nss (n=4..7) — s(7.1)
0xD2D4 REG_AX_PWR_BY_RATE_TABLE5
  [8n-58:8n-64] r_txagc_nonlegacy_mcs{n}_1nss (n=8..11) — s(7.1)
0xD2D8 REG_AX_PWR_BY_RATE_TABLE6
  [30:24] r_txagc_nonlegacy_dcm_mcs4_1nss — s(7.1)
  [22:16] r_txagc_nonlegacy_dcm_mcs3_1nss — s(7.1)
  [14:8] r_txagc_nonlegacy_dcm_mcs1_1nss — s(7.1)
  [6:0] r_txagc_nonlegacy_dcm_mcs0_1nss — s(7.1)
0xD2EC REG_AX_PWR_LMT_TABLE0
  [6:0] r_txagc_max_cck_1tx_BW20M — s(7.1)
0xD2F0 REG_AX_PWR_LMT_TABLE1
  [22:16] r_txagc_max_1tx_BW20_0 — s(7.1)
  [6:0] r_txagc_max_legacy_non_dup_1tx — s(7.1)
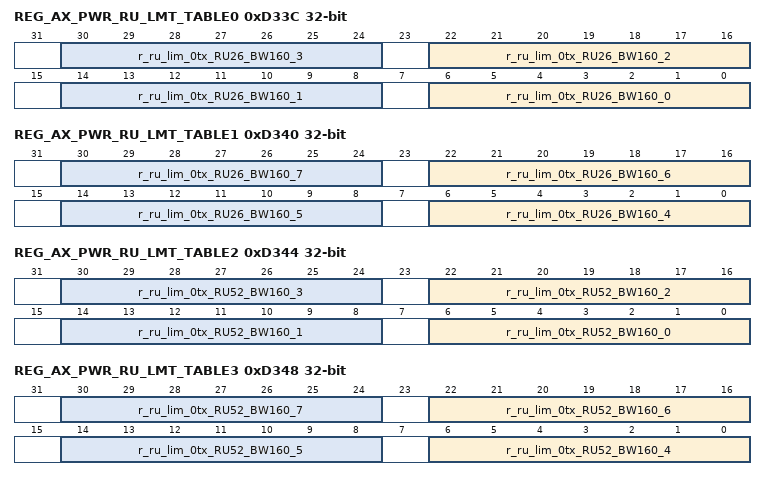
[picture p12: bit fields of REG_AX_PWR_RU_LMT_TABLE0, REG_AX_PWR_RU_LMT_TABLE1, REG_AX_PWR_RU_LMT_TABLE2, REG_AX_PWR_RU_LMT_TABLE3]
0xD33C REG_AX_PWR_RU_LMT_TABLE0
  [8n+6:8n] r_ru_lim_0tx_RU26_BW160_{n} (n=0..3) — s(7.1)
0xD340 REG_AX_PWR_RU_LMT_TABLE1
  [8n-26:8n-32] r_ru_lim_0tx_RU26_BW160_{n} (n=4..7) — s(7.1)
0xD344 REG_AX_PWR_RU_LMT_TABLE2
  [8n+6:8n] r_ru_lim_0tx_RU52_BW160_{n} (n=0..3) — s(7.1)
0xD348 REG_AX_PWR_RU_LMT_TABLE3
  [8n-26:8n-32] r_ru_lim_0tx_RU52_BW160_{n} (n=4..7) — s(7.1)
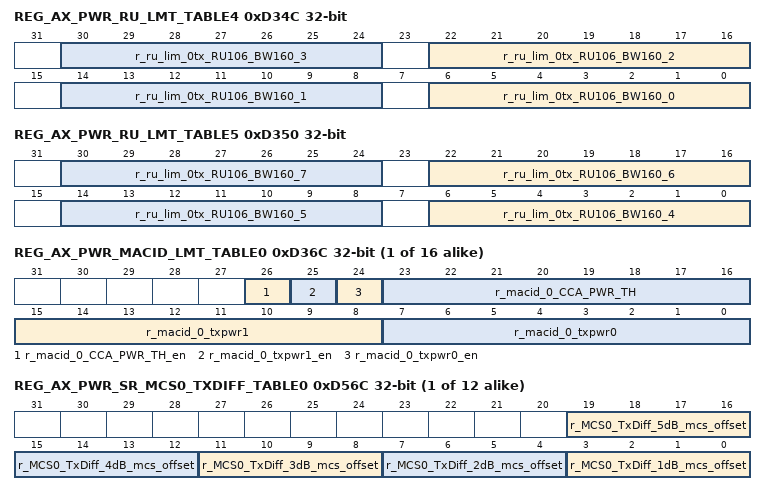
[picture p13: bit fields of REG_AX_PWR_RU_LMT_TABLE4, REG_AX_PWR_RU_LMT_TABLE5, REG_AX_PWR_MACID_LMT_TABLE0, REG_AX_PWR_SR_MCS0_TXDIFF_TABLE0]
0xD34C REG_AX_PWR_RU_LMT_TABLE4
  [8n+6:8n] r_ru_lim_0tx_RU106_BW160_{n} (n=0..3) — s(7.1)
0xD350 REG_AX_PWR_RU_LMT_TABLE5
  [8n-26:8n-32] r_ru_lim_0tx_RU106_BW160_{n} (n=4..7) — s(7.1)
{0xD36C+4i} REG_AX_PWR_MACID_LMT_TABLE{i} (i=0..15)
  [26] r_macid_{i}_CCA_PWR_TH_en — u(1.0)
  [25] r_macid_{i}_txpwr1_en — u(1.0)
  [24] r_macid_{i}_txpwr0_en — u(1.0)
  [23:16] r_macid_{i}_CCA_PWR_TH — s(8.1)
  [15:8] r_macid_{i}_txpwr1 — s(8.1)
  [7:0] r_macid_{i}_txpwr0 — s(8.1)
{0xD56C+0x10*i} REG_AX_PWR_SR_MCS{i}_TXDIFF_TABLE0 (i=0..11)
  [4n-1:4n-4] r_MCS{i}_TxDiff_{n}dB_mcs_offset (n=1..5) — U(4.0) mcs0~11
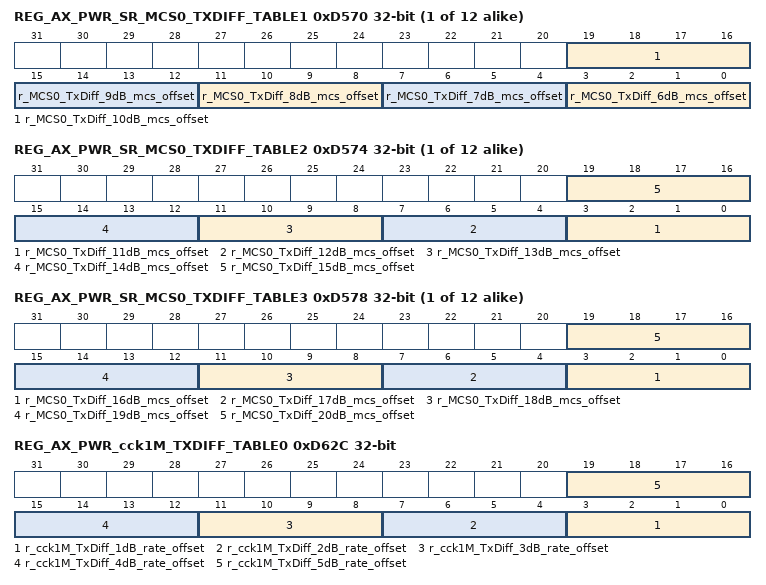
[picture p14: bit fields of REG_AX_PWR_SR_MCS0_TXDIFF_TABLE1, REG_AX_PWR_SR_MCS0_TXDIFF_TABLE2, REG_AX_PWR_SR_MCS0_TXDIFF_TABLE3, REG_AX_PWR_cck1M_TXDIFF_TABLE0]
{0xD570+0x10*i} REG_AX_PWR_SR_MCS{i}_TXDIFF_TABLE1 (i=0..11)
  [4n-21:4n-24] r_MCS{i}_TxDiff_{n}dB_mcs_offset (n=6..10) — U(4.0) mcs0~11
{0xD574+0x10*i} REG_AX_PWR_SR_MCS{i}_TXDIFF_TABLE2 (i=0..11)
  [4n-41:4n-44] r_MCS{i}_TxDiff_{n}dB_mcs_offset (n=11..15) — U(4.0) mcs0~11
{0xD578+0x10*i} REG_AX_PWR_SR_MCS{i}_TXDIFF_TABLE3 (i=0..11)
  [4n-61:4n-64] r_MCS{i}_TxDiff_{n}dB_mcs_offset (n=16..20) — U(4.0) mcs0~11
0xD62C REG_AX_PWR_cck1M_TXDIFF_TABLE0
  [4n-1:4n-4] r_cck1M_TxDiff_{n}dB_rate_offset (n=1..5) — U(4.0) cck 0~3, 0-cck1M,1=cck2M,2=cck5p5M,3=cck11M
0xD630 REG_AX_PWR_cck1M_TXDIFF_TABLE1
  [4n-21:4n-24] r_cck1M_TxDiff_{n}dB_rate_offset (n=6..10) — U(4.0) cck 0~3, 0-cck1M,1=cck2M,2=cck5p5M,3=cck11M
0xD634 REG_AX_PWR_cck1M_TXDIFF_TABLE2
  [4n-41:4n-44] r_cck1M_TxDiff_{n}dB_rate_offset (n=11..15) — U(4.0) cck 0~3, 0-cck1M,1=cck2M,2=cck5p5M,3=cck11M
0xD638 REG_AX_PWR_cck1M_TXDIFF_TABLE3
  [4n-61:4n-64] r_cck1M_TxDiff_{n}dB_rate_offset (n=16..20) — U(4.0) cck 0~3, 0-cck1M,1=cck2M,2=cck5p5M,3=cck11M
0xD63C REG_AX_PWR_cck2M_TXDIFF_TABLE0
  [4n-1:4n-4] r_cck2M_TxDiff_{n}dB_rate_offset (n=1..5) — U(4.0) cck 0~3, 0-cck1M,1=cck2M,2=cck5p5M,3=cck11M
0xD640 REG_AX_PWR_cck2M_TXDIFF_TABLE1
  [4n-21:4n-24] r_cck2M_TxDiff_{n}dB_rate_offset (n=6..10) — U(4.0) cck 0~3, 0-cck1M,1=cck2M,2=cck5p5M,3=cck11M
0xD644 REG_AX_PWR_cck2M_TXDIFF_TABLE2
  [4n-41:4n-44] r_cck2M_TxDiff_{n}dB_rate_offset (n=11..15) — U(4.0) cck 0~3, 0-cck1M,1=cck2M,2=cck5p5M,3=cck11M
0xD648 REG_AX_PWR_cck2M_TXDIFF_TABLE3
  [4n-61:4n-64] r_cck2M_TxDiff_{n}dB_rate_offset (n=16..20) — U(4.0) cck 0~3, 0-cck1M,1=cck2M,2=cck5p5M,3=cck11M
0xD64C REG_AX_PWR_cck5p5M_TXDIFF_TABLE0
  [4n-1:4n-4] r_cck5p5M_TxDiff_{n}dB_rate_offset (n=1..5) — U(4.0) cck 0~3, 0-cck1M,1=cck2M,2=cck5p5M,3=cck11M
0xD650 REG_AX_PWR_cck5p5M_TXDIFF_TABLE1
  [4n-21:4n-24] r_cck5p5M_TxDiff_{n}dB_rate_offset (n=6..10) — U(4.0) cck 0~3, 0-cck1M,1=cck2M,2=cck5p5M,3=cck11M
0xD654 REG_AX_PWR_cck5p5M_TXDIFF_TABLE2
  [4n-41:4n-44] r_cck5p5M_TxDiff_{n}dB_rate_offset (n=11..15) — U(4.0) cck 0~3, 0-cck1M,1=cck2M,2=cck5p5M,3=cck11M
0xD658 REG_AX_PWR_cck5p5M_TXDIFF_TABLE3
  [4n-61:4n-64] r_cck5p5M_TxDiff_{n}dB_rate_offset (n=16..20) — U(4.0) cck 0~3, 0-cck1M,1=cck2M,2=cck5p5M,3=cck11M
0xD65C REG_AX_PWR_cck11M_TXDIFF_TABLE0
  [4n-1:4n-4] r_cck11M_TxDiff_{n}dB_rate_offset (n=1..5) — U(4.0) cck 0~3, 0-cck1M,1=cck2M,2=cck5p5M,3=cck11M
0xD660 REG_AX_PWR_cck11M_TXDIFF_TABLE1
  [4n-21:4n-24] r_cck11M_TxDiff_{n}dB_rate_offset (n=6..10) — U(4.0) cck 0~3, 0-cck1M,1=cck2M,2=cck5p5M,3=cck11M
0xD664 REG_AX_PWR_cck11M_TXDIFF_TABLE2
  [4n-41:4n-44] r_cck11M_TxDiff_{n}dB_rate_offset (n=11..15) — U(4.0) cck 0~3, 0-cck1M,1=cck2M,2=cck5p5M,3=cck11M
0xD668 REG_AX_PWR_cck11M_TXDIFF_TABLE3
  [4n-61:4n-64] r_cck11M_TxDiff_{n}dB_rate_offset (n=16..20) — U(4.0) cck 0~3, 0-cck1M,1=cck2M,2=cck5p5M,3=cck11M
0xD66C REG_AX_PWR_legacy6M_TXDIFF_TABLE0
  [4n-1:4n-4] r_legacy6M_TxDiff_{n}dB_rate_offset (n=1..5) — U(4.0) legacy 4~11,4=legacy6M,5=legacy9M,6=legacy12M,7=legacy18M,8=legacy24M,9=legacy36M,10=legacy48M,11=legacy54M
0xD670 REG_AX_PWR_legacy6M_TXDIFF_TABLE1
  [4n-21:4n-24] r_legacy6M_TxDiff_{n}dB_rate_offset (n=6..10) — U(4.0) legacy 4~11,4=legacy6M,5=legacy9M,6=legacy12M,7=legacy18M,8=legacy24M,9=legacy36M,10=legacy48M,11=legacy54M
0xD674 REG_AX_PWR_legacy6M_TXDIFF_TABLE2
  [4n-41:4n-44] r_legacy6M_TxDiff_{n}dB_rate_offset (n=11..15) — U(4.0) legacy 4~11,4=legacy6M,5=legacy9M,6=legacy12M,7=legacy18M,8=legacy24M,9=legacy36M,10=legacy48M,11=legacy54M
0xD678 REG_AX_PWR_legacy6M_TXDIFF_TABLE3
  [4n-61:4n-64] r_legacy6M_TxDiff_{n}dB_rate_offset (n=16..20) — U(4.0) legacy 4~11,4=legacy6M,5=legacy9M,6=legacy12M,7=legacy18M,8=legacy24M,9=legacy36M,10=legacy48M,11=legacy54M
0xD67C REG_AX_PWR_legacy9M_TXDIFF_TABLE0
  [4n-1:4n-4] r_legacy9M_TxDiff_{n}dB_rate_offset (n=1..5) — U(4.0) legacy 4~11,4=legacy6M,5=legacy9M,6=legacy12M,7=legacy18M,8=legacy24M,9=legacy36M,10=legacy48M,11=legacy54M
0xD680 REG_AX_PWR_legacy9M_TXDIFF_TABLE1
  [4n-21:4n-24] r_legacy9M_TxDiff_{n}dB_rate_offset (n=6..10) — U(4.0) legacy 4~11,4=legacy6M,5=legacy9M,6=legacy12M,7=legacy18M,8=legacy24M,9=legacy36M,10=legacy48M,11=legacy54M
0xD684 REG_AX_PWR_legacy9M_TXDIFF_TABLE2
  [4n-41:4n-44] r_legacy9M_TxDiff_{n}dB_rate_offset (n=11..15) — U(4.0) legacy 4~11,4=legacy6M,5=legacy9M,6=legacy12M,7=legacy18M,8=legacy24M,9=legacy36M,10=legacy48M,11=legacy54M
0xD688 REG_AX_PWR_legacy9M_TXDIFF_TABLE3
  [4n-61:4n-64] r_legacy9M_TxDiff_{n}dB_rate_offset (n=16..20) — U(4.0) legacy 4~11,4=legacy6M,5=legacy9M,6=legacy12M,7=legacy18M,8=legacy24M,9=legacy36M,10=legacy48M,11=legacy54M
0xD68C REG_AX_PWR_legacy12M_TXDIFF_TABLE0
  [4n-1:4n-4] r_legacy12M_TxDiff_{n}dB_rate_offset (n=1..5) — U(4.0) legacy 4~11,4=legacy6M,5=legacy9M,6=legacy12M,7=legacy18M,8=legacy24M,9=legacy36M,10=legacy48M,11=legacy54M
0xD690 REG_AX_PWR_legacy12M_TXDIFF_TABLE1
  [4n-21:4n-24] r_legacy12M_TxDiff_{n}dB_rate_offset (n=6..10) — U(4.0) legacy 4~11,4=legacy6M,5=legacy9M,6=legacy12M,7=legacy18M,8=legacy24M,9=legacy36M,10=legacy48M,11=legacy54M
0xD694 REG_AX_PWR_legacy12M_TXDIFF_TABLE2
  [4n-41:4n-44] r_legacy12M_TxDiff_{n}dB_rate_offset (n=11..15) — U(4.0) legacy 4~11,4=legacy6M,5=legacy9M,6=legacy12M,7=legacy18M,8=legacy24M,9=legacy36M,10=legacy48M,11=legacy54M
0xD698 REG_AX_PWR_legacy12M_TXDIFF_TABLE3
  [4n-61:4n-64] r_legacy12M_TxDiff_{n}dB_rate_offset (n=16..20) — U(4.0) legacy 4~11,4=legacy6M,5=legacy9M,6=legacy12M,7=legacy18M,8=legacy24M,9=legacy36M,10=legacy48M,11=legacy54M
0xD69C REG_AX_PWR_legacy18M_TXDIFF_TABLE0
  [4n-1:4n-4] r_legacy18M_TxDiff_{n}dB_rate_offset (n=1..5) — U(4.0) legacy 4~11,4=legacy6M,5=legacy9M,6=legacy12M,7=legacy18M,8=legacy24M,9=legacy36M,10=legacy48M,11=legacy54M
0xD6A0 REG_AX_PWR_legacy18M_TXDIFF_TABLE1
  [4n-21:4n-24] r_legacy18M_TxDiff_{n}dB_rate_offset (n=6..10) — U(4.0) legacy 4~11,4=legacy6M,5=legacy9M,6=legacy12M,7=legacy18M,8=legacy24M,9=legacy36M,10=legacy48M,11=legacy54M
0xD6A4 REG_AX_PWR_legacy18M_TXDIFF_TABLE2
  [4n-41:4n-44] r_legacy18M_TxDiff_{n}dB_rate_offset (n=11..15) — U(4.0) legacy 4~11,4=legacy6M,5=legacy9M,6=legacy12M,7=legacy18M,8=legacy24M,9=legacy36M,10=legacy48M,11=legacy54M
0xD6A8 REG_AX_PWR_legacy18M_TXDIFF_TABLE3
  [4n-61:4n-64] r_legacy18M_TxDiff_{n}dB_rate_offset (n=16..20) — U(4.0) legacy 4~11,4=legacy6M,5=legacy9M,6=legacy12M,7=legacy18M,8=legacy24M,9=legacy36M,10=legacy48M,11=legacy54M
0xD6AC REG_AX_PWR_legacy24M_TXDIFF_TABLE0
  [4n-1:4n-4] r_legacy24M_TxDiff_{n}dB_rate_offset (n=1..5) — U(4.0) legacy 4~11,4=legacy6M,5=legacy9M,6=legacy12M,7=legacy18M,8=legacy24M,9=legacy36M,10=legacy48M,11=legacy54M
0xD6B0 REG_AX_PWR_legacy24M_TXDIFF_TABLE1
  [4n-21:4n-24] r_legacy24M_TxDiff_{n}dB_rate_offset (n=6..10) — U(4.0) legacy 4~11,4=legacy6M,5=legacy9M,6=legacy12M,7=legacy18M,8=legacy24M,9=legacy36M,10=legacy48M,11=legacy54M
0xD6B4 REG_AX_PWR_legacy24M_TXDIFF_TABLE2
  [4n-41:4n-44] r_legacy24M_TxDiff_{n}dB_rate_offset (n=11..15) — U(4.0) legacy 4~11,4=legacy6M,5=legacy9M,6=legacy12M,7=legacy18M,8=legacy24M,9=legacy36M,10=legacy48M,11=legacy54M
0xD6B8 REG_AX_PWR_legacy24M_TXDIFF_TABLE3
  [4n-61:4n-64] r_legacy24M_TxDiff_{n}dB_rate_offset (n=16..20) — U(4.0) legacy 4~11,4=legacy6M,5=legacy9M,6=legacy12M,7=legacy18M,8=legacy24M,9=legacy36M,10=legacy48M,11=legacy54M
0xD6BC REG_AX_PWR_legacy36M_TXDIFF_TABLE0
  [4n-1:4n-4] r_legacy36M_TxDiff_{n}dB_rate_offset (n=1..5) — U(4.0) legacy 4~11,4=legacy6M,5=legacy9M,6=legacy12M,7=legacy18M,8=legacy24M,9=legacy36M,10=legacy48M,11=legacy54M
0xD6C0 REG_AX_PWR_legacy36M_TXDIFF_TABLE1
  [4n-21:4n-24] r_legacy36M_TxDiff_{n}dB_rate_offset (n=6..10) — U(4.0) legacy 4~11,4=legacy6M,5=legacy9M,6=legacy12M,7=legacy18M,8=legacy24M,9=legacy36M,10=legacy48M,11=legacy54M
0xD6C4 REG_AX_PWR_legacy36M_TXDIFF_TABLE2
  [4n-41:4n-44] r_legacy36M_TxDiff_{n}dB_rate_offset (n=11..15) — U(4.0) legacy 4~11,4=legacy6M,5=legacy9M,6=legacy12M,7=legacy18M,8=legacy24M,9=legacy36M,10=legacy48M,11=legacy54M
0xD6C8 REG_AX_PWR_legacy36M_TXDIFF_TABLE3
  [4n-61:4n-64] r_legacy36M_TxDiff_{n}dB_rate_offset (n=16..20) — U(4.0) legacy 4~11,4=legacy6M,5=legacy9M,6=legacy12M,7=legacy18M,8=legacy24M,9=legacy36M,10=legacy48M,11=legacy54M
0xD6CC REG_AX_PWR_legacy48M_TXDIFF_TABLE0
  [4n-1:4n-4] r_legacy48M_TxDiff_{n}dB_rate_offset (n=1..5) — U(4.0) legacy 4~11,4=legacy6M,5=legacy9M,6=legacy12M,7=legacy18M,8=legacy24M,9=legacy36M,10=legacy48M,11=legacy54M
0xD6D0 REG_AX_PWR_legacy48M_TXDIFF_TABLE1
  [4n-21:4n-24] r_legacy48M_TxDiff_{n}dB_rate_offset (n=6..10) — U(4.0) legacy 4~11,4=legacy6M,5=legacy9M,6=legacy12M,7=legacy18M,8=legacy24M,9=legacy36M,10=legacy48M,11=legacy54M
0xD6D4 REG_AX_PWR_legacy48M_TXDIFF_TABLE2
  [4n-41:4n-44] r_legacy48M_TxDiff_{n}dB_rate_offset (n=11..15) — U(4.0) legacy 4~11,4=legacy6M,5=legacy9M,6=legacy12M,7=legacy18M,8=legacy24M,9=legacy36M,10=legacy48M,11=legacy54M
0xD6D8 REG_AX_PWR_legacy48M_TXDIFF_TABLE3
  [4n-61:4n-64] r_legacy48M_TxDiff_{n}dB_rate_offset (n=16..20) — U(4.0) legacy 4~11,4=legacy6M,5=legacy9M,6=legacy12M,7=legacy18M,8=legacy24M,9=legacy36M,10=legacy48M,11=legacy54M
0xD6DC REG_AX_PWR_legacy54M_TXDIFF_TABLE0
  [4n-1:4n-4] r_legacy54M_TxDiff_{n}dB_rate_offset (n=1..5) — U(4.0) legacy 4~11,4=legacy6M,5=legacy9M,6=legacy12M,7=legacy18M,8=legacy24M,9=legacy36M,10=legacy48M,11=legacy54M
0xD6E0 REG_AX_PWR_legacy54M_TXDIFF_TABLE1
  [4n-21:4n-24] r_legacy54M_TxDiff_{n}dB_rate_offset (n=6..10) — U(4.0) legacy 4~11,4=legacy6M,5=legacy9M,6=legacy12M,7=legacy18M,8=legacy24M,9=legacy36M,10=legacy48M,11=legacy54M
0xD6E4 REG_AX_PWR_legacy54M_TXDIFF_TABLE2
  [4n-41:4n-44] r_legacy54M_TxDiff_{n}dB_rate_offset (n=11..15) — U(4.0) legacy 4~11,4=legacy6M,5=legacy9M,6=legacy12M,7=legacy18M,8=legacy24M,9=legacy36M,10=legacy48M,11=legacy54M
0xD6E8 REG_AX_PWR_legacy54M_TXDIFF_TABLE3
  [4n-61:4n-64] r_legacy54M_TxDiff_{n}dB_rate_offset (n=16..20) — U(4.0) legacy 4~11,4=legacy6M,5=legacy9M,6=legacy12M,7=legacy18M,8=legacy24M,9=legacy36M,10=legacy48M,11=legacy54M
0xD800 REG_AX_PWR_TCM_WRAPPER_CR0
  [31] r_bf_1sts_ant_sel_a, [30:27] r_grp_2tx_path_en, [26:23] r_grp_1tx_path_en, [22:19] r_force_macid_ant_path_en_val, [18:15] r_fc_path_en, [14:11] r_bf_2sts_path_en, [10:7] r_bf_1sts_path_en, [6:0] r_usr_list_tbl_ra
0xD804 REG_AX_PWR_TCM_WRAPPER_CR1
  [31:28] r_norm_1sts_path_en, [27:24] r_hang_proof_path_en, [4n-9:4n-12] r_grp_{n}tx_path_en (n=3..8)
0xD808 REG_AX_PWR_TCM_WRAPPER_CR2
  [31:30] r_bf_1sts_path_map_a, [29:27] r_force_par_mode_val, [26:24] r_force_macid_ant_spatial_expan_num_val, [23:21] r_fc_spatial_expan_num, [20:18] r_fc_ntx, [17:15] r_bf_2sts_spatial_expan_num, [14:12] r_bf_1sts_spatial_expan_num, [11:8] r_resp_2sts_path_en, [7:4] r_resp_1sts_path_en, [3:0] r_norm_2sts_path_en
0xD80C REG_AX_PWR_TCM_WRAPPER_CR3
  [31:30] r_bf_1sts_path_map_b, [29:27] r_norm_1sts_spatial_expan_num, [26:24] r_hang_proof_spatial_expan_num, [3n-1:3n-3] r_grp_{n}tx_spatial_expan_num (n=1..8)
0xD810 REG_AX_PWR_TCM_WRAPPER_CR4
  [31] r_bf_1sts_ant_sel_b, [30:29] r_force_macid_ant_map_a_val, [28:27] r_fc_path_map_d, [26:25] r_fc_path_map_c, [24:23] r_fc_path_map_b, [22:21] r_fc_path_map_a, [20:19] r_bf_2sts_path_map_d, [18:17] r_bf_2sts_path_map_c, [16:15] r_bf_2sts_path_map_b, [14:13] r_bf_2sts_path_map_a, [12:11] r_bf_1sts_path_map_d, [10:9] r_bf_1sts_path_map_c, [8:6] r_resp_2sts_spatial_expan_num, [5:3] r_resp_1sts_spatial_expan_num, [2:0] r_norm_2sts_spatial_expan_num
0xD814 REG_AX_PWR_TCM_WRAPPER_CR5
  [8n-1:8n-2] r_grp_{n}tx_path_map_a (n=1..4), [29:28] r_grp_3tx_path_map_d, [27:26] r_grp_3tx_path_map_c, [25:24] r_grp_3tx_path_map_b, [21:20] r_grp_2tx_path_map_d, [19:18] r_grp_2tx_path_map_c, [17:16] r_grp_2tx_path_map_b, [13:12] r_grp_1tx_path_map_d, [11:10] r_grp_1tx_path_map_c, [9:8] r_grp_1tx_path_map_b, [5:4] r_force_macid_ant_map_d_val, [3:2] r_force_macid_ant_map_c_val, [1:0] r_force_macid_ant_map_b_val
0xD818 REG_AX_PWR_TCM_WRAPPER_CR6
  [8n-33:8n-34] r_grp_{n}tx_path_map_a (n=5..8), [8n-27:8n-28] r_grp_{n}tx_path_map_d (n=4..7), [8n-29:8n-30] r_grp_{n}tx_path_map_c (n=4..7), [8n-31:8n-32] r_grp_{n}tx_path_map_b (n=4..7)
0xD81C REG_AX_PWR_TCM_WRAPPER_CR7
  [31:30] r_resp_1sts_path_map_a, [29:28] r_norm_2sts_path_map_d, [27:26] r_norm_2sts_path_map_c, [25:24] r_norm_2sts_path_map_b, [23:22] r_norm_2sts_path_map_a, [21:20] r_norm_1sts_path_map_d, [19:18] r_norm_1sts_path_map_c, [17:16] r_norm_1sts_path_map_b, [15:14] r_norm_1sts_path_map_a, [13:12] r_hang_proof_path_map_d, [11:10] r_hang_proof_path_map_c, [9:8] r_hang_proof_path_map_b, [7:6] r_hang_proof_path_map_a, [5:4] r_grp_8tx_path_map_d, [3:2] r_grp_8tx_path_map_c, [1:0] r_grp_8tx_path_map_b
0xD820 REG_AX_PWR_TCM_WRAPPER_CR8
  [31] r_fc_ntx_en, [30] r_fc_ant_sel_d_en, [29] r_fc_ant_sel_d, [28] r_fc_ant_sel_c_en, [27] r_fc_ant_sel_c, [26] r_fc_ant_sel_b_en, [25] r_fc_ant_sel_b, [24] r_fc_ant_sel_a_en, [23] r_fc_ant_sel_a, [22] r_clr_proof_cnt, [21] r_cbw80p80_en, [20] r_bypass_ant_sel_hetb_bw80p80_en, [19] r_bf_2sts_ant_sel_d, [18] r_bf_2sts_ant_sel_c, [17] r_bf_2sts_ant_sel_b, [16] r_bf_2sts_ant_sel_a, [15] r_bf_1sts_ant_sel_d, [14] r_bf_1sts_ant_sel_c, [13:12] r_resp_2sts_path_map_d, [11:10] r_resp_2sts_path_map_c, [9:8] r_resp_2sts_path_map_b, [7:6] r_resp_2sts_path_map_a, [5:4] r_resp_1sts_path_map_d, [3:2] r_resp_1sts_path_map_c, [1:0] r_resp_1sts_path_map_b
0xD824 REG_AX_PWR_TCM_WRAPPER_CR9
  [31] r_grp_2tx_ant_sel_c, [30] r_grp_2tx_ant_sel_b, [29] r_grp_2tx_ant_sel_a, [28] r_grp_1tx_ant_sel_d, [27] r_grp_1tx_ant_sel_c, [26] r_grp_1tx_ant_sel_b, [25] r_grp_1tx_ant_sel_a, [24] r_force_par_mode_on, [23] r_force_macid_input_mumimo_nsts_hang_proof_en_val, [22] r_force_macid_input_mumimo_nsts_hang_proof_en_on, [21] r_force_macid_hang_proof_en_val, [20] r_force_macid_hang_proof_en_on, [19] r_force_macid_ant_spatial_expan_num_on, [18] r_force_macid_ant_sel_d_val, [17] r_force_macid_ant_sel_d_on, [16] r_force_macid_ant_sel_c_val, [15] r_force_macid_ant_sel_c_on, [14] r_force_macid_ant_sel_b_val, [13] r_force_macid_ant_sel_b_on, [12] r_force_macid_ant_sel_a_val, [11] r_force_macid_ant_sel_a_on, [10] r_force_macid_ant_path_en_on, [9] r_force_macid_ant_map_d_on, [8] r_force_macid_ant_map_c_on, [7] r_force_macid_ant_map_b_on, [6] r_force_macid_ant_map_a_on, [5] r_fc_spatial_expan_num_en, [4] r_fc_path_map_d_en, [3] r_fc_path_map_c_en, [2] r_fc_path_map_b_en, [1] r_fc_path_map_a_en, [0] r_fc_path_en_en
0xD828 REG_AX_PWR_TCM_WRAPPER_CR10
  [31] r_input_mumimo_nsts_hang_proof_en, [30] r_hang_proof_opt, [29] r_hang_proof_en, [28] r_hang_proof_ant_sel_d, [27] r_hang_proof_ant_sel_c, [26] r_hang_proof_ant_sel_b, [25] r_hang_proof_ant_sel_a, [4n-8] r_grp_{n}tx_ant_sel_d (n=2..8), [4n-9] r_grp_{n}tx_ant_sel_c (n=3..8), [4n-10] r_grp_{n}tx_ant_sel_b (n=3..8), [4n-11] r_grp_{n}tx_ant_sel_a (n=3..8)
0xD82C REG_AX_PWR_TCM_WRAPPER_CR11
  [20] r_force_hang_proof_on, [19] r_usr_list_tbl_rd, [18] r_resp_2stsant_sel_d, [17] r_resp_2stsant_sel_c, [16] r_resp_2stsant_sel_b, [15] r_resp_2stsant_sel_a, [14] r_resp_1stsant_sel_d, [13] r_resp_1stsant_sel_c, [12] r_resp_1stsant_sel_b, [11] r_resp_1stsant_sel_a, [10] r_norm_2stsant_sel_d, [9] r_norm_2stsant_sel_c, [8] r_norm_2stsant_sel_b, [7] r_norm_2stsant_sel_a, [6] r_norm_1stsant_sel_d, [5] r_norm_1stsant_sel_c, [4] r_norm_1stsant_sel_b, [3] r_norm_1stsant_sel_a, [2] r_n_tx_cal_mod_hang_proof, [1] r_n_tx_cal_mod, [0] r_input_mumimo_nsts_hang_proof_opt
0xD830 REG_AX_PWR_TCM_WRAPPER_CR12
  [31:26] r_force_pwrsr_txpwr_pd_val, [25:18] r_force_pwrcom_ru_alloc_val, [17:9] r_force_pwrul_rpl_val, [8:0] r_force_pwrul_rpl_up_val
0xD834 REG_AX_PWR_TCM_WRAPPER_CR13
  [31:28] r_dbg_ant_sel, [27:22] r_force_pwrsr_txpwr_toler_val, [21:15] r_force_pwrul_tar_rssi_val, [14:8] r_force_pwrcom_macid_val, [7:0] r_force_pwrru_ch20_with_data_val
0xD838 REG_AX_PWR_TCM_WRAPPER_CR14
  [31:29] r_force_pwrcom_ctrl_val, [28:26] r_force_pwrant_nsts_val, [25:23] r_force_macid_pwr_mode_val, [22:19] r_force_pwrcom_txsc_val, [18:15] r_force_pwrcom_ppdu_type_val, [14:11] r_force_out_pwrcom_max_mcs_val, [10:6] r_force_pwrcom_mcs_val, [5:0] r_force_pwrul_ap_tx_pwr_val
0xD83C REG_AX_PWR_TCM_WRAPPER_CR15
  [31] r_force_macid_txbf_en_val, [30] r_force_macid_txbf_en_on, [29] r_force_macid_resp_en_val, [28] r_force_macid_resp_en_on, [27] r_force_macid_pwr_mode_on, [26] r_force_macid_norm_en_val, [25] r_force_macid_norm_en_on, [24] r_force_macid_ndp_en_val, [23] r_force_macid_ndp_en_on, [22] r_force_macid_mumimo_en_val, [21] r_force_macid_mumimo_en_on, [20] r_force_macid_cca_th_allow_val, [19] r_force_macid_cca_th_allow_on, [18] r_force_cca_th_allow_val, [17] r_force_cca_th_allow_on, [16] r_clr_ant_set, [15] r_ant_sel_dbg_en, [8:7] r_force_pwrcom_precoding_mode_idx_val, [6:5] r_force_pwrcom_dbw_idx_val, [4:3] r_force_pwrcom_cbw_idx_val, [2:0] r_force_pwrru_grp_ntx_val
0xD840 REG_AX_PWR_TCM_WRAPPER_CR16
  [31] r_force_pwrul_rpl_up_en_on, [30] r_force_pwrul_rpl_on, [29] r_force_pwrul_ap_tx_pwr_on, [28] r_force_pwrtssi_fast_mode_en_val, [27] r_force_pwrtssi_fast_mode_en_on, [26] r_force_pwrsr_txpwr_toler_on, [25] r_force_pwrsr_txpwr_pd_on, [24] r_force_pwrru_grp_ntx_on, [23] r_force_pwrru_ch20_with_data_on, [22] r_force_pwrcom_txsc_on, [21] r_force_pwrcom_stbc_en_val, [20] r_force_pwrcom_stbc_en_on, [19] r_force_pwrcom_rx_lte_val, [18] r_force_pwrcom_rx_lte_on, [17] r_force_pwrcom_ru_alloc_on, [16] r_force_pwrcom_precoding_mode_idx_on, [15] r_force_pwrcom_ppdu_type_on, [14] r_force_pwrcom_mcs_on, [13] r_force_pwrcom_macid_on, [12] r_force_pwrcom_dcm_val, [11] r_force_pwrcom_dcm_on, [10] r_force_pwrcom_dbw_idx_on, [9] r_force_pwrcom_ctrl_reg_val, [8] r_force_pwrcom_ctrl_reg_on, [7] r_force_pwrcom_ctrl_on, [6] r_force_pwrcom_cbw_idx_on, [5] r_force_pwrant_nsts_on, [4] r_force_pwrant_ndp_en_val, [3] r_force_pwrant_ndp_en_on, [2] r_force_pwrant_active_tx_en_val, [1] r_force_pwrant_active_tx_en_on, [0] r_force_out_pwrcom_max_mcs_on
0xD844 REG_AX_PWR_TCM_WRAPPER_CR17
  [9] r_tssi_ctrl_mac_pwrcom_ch20_with_data_bit_rev, [8] r_tssi_ctrl_mac_pwrcom_ch20_with_data_bit_inv, [7] r_sr_mcs_mask_dis, [6] r_pwrru_ch20_with_data_hang_proof_en, [5] r_mumimo_apply_pwrlimbf_en, [4] r_heru_mask_dis, [3] r_heru_ch20_with_data_from_f2p_dis, [2] r_force_pwrul_tar_rssi_on, [1] r_force_pwrul_rpl_up_on, [0] r_force_pwrul_rpl_up_en_val
0xD848 REG_AX_PWR_TCM_WRAPPER_CR18
  [28] r_ru_alloc_dbw160_fix_en, [27] r_pwrtssict_tx_bandedge_cfg_force_out_on, [26] r_pwrtssict_tssi_msr_athestf_force_out_val, [25] r_pwrtssict_tssi_msr_athestf_force_out_on, [24] r_pwrtssict_tssi_fast_mode_en_force_out_val, [23] r_pwrtssict_tssi_fast_mode_en_force_out_on, [22] r_pwrtssict_tssi_diff_seg0_db_force_out_on, [21] r_pwrtssict_pwr_ofst_seg0_db_force_out_on, [20] r_MAC_def_legacy_rate_idx_begin_at_4_on, [19:18] r_pwrtssict_tx_bandedge_cfg_force_out_val, [17:9] r_pwrtssict_tssi_diff_seg0_db_force_out_val, [8:0] r_pwrtssict_pwr_ofst_seg0_db_force_out_val
0xD908 REG_AX_PWR_TSSI_TABLE0
  [8n+7:8n] r_bandedge_nonzero_cfg_sbw160_{n} (n=0..3)
0xD90C REG_AX_PWR_TSSI_TABLE1
  [8n-25:8n-32] r_bandedge_nonzero_cfg_sbw160_{n} (n=4..7)
0xD910 REG_AX_PWR_TSSI_TABLE2
  [31:24] r_bandedge_nonzero_cfg_sbw80_0, [23:16] r_bandedge_nonzero_cfg_sbw40_1, [15:8] r_bandedge_nonzero_cfg_sbw40_0, [7:0] r_bandedge_nonzero_cfg_sbw20
0xD914 REG_AX_PWR_TSSI_TABLE3
  [31:24] r_bandedge_zero_cfg_sbw160_0, [23:16] r_bandedge_nonzero_cfg_sbw80_3, [15:8] r_bandedge_nonzero_cfg_sbw80_2, [7:0] r_bandedge_nonzero_cfg_sbw80_1
0xD918 REG_AX_PWR_TSSI_TABLE4
  [8n-1:8n-8] r_bandedge_zero_cfg_sbw160_{n} (n=1..4)
0xD91C REG_AX_PWR_TSSI_TABLE5
  [31:24] r_bandedge_zero_cfg_sbw20, [23:16] r_bandedge_zero_cfg_sbw160_7, [15:8] r_bandedge_zero_cfg_sbw160_6, [7:0] r_bandedge_zero_cfg_sbw160_5
0xD920 REG_AX_PWR_TSSI_TABLE6
  [31:24] r_bandedge_zero_cfg_sbw80_1, [23:16] r_bandedge_zero_cfg_sbw80_0, [15:8] r_bandedge_zero_cfg_sbw40_1, [7:0] r_bandedge_zero_cfg_sbw40_0
0xD924 REG_AX_PWR_TSSI_TABLE7
  [31:24] r_bmode_init_ofst_seg0_db, [23:16] r_bmode_init_diff_seg0_db, [15:8] r_bandedge_zero_cfg_sbw80_3, [7:0] r_bandedge_zero_cfg_sbw80_2
0xD928 REG_AX_PWR_TSSI_TABLE8
  [8n+7:8n] r_cbw_sub20_{n} (n=0..3)
0xD92C REG_AX_PWR_TSSI_TABLE9
  [8n-25:8n-32] r_cbw_sub20_{n} (n=4..7)
0xD930 REG_AX_PWR_TSSI_TABLE10
  [31:24] r_ch_comb_ofst_bandedge_nonzero_bw40, [23:16] r_ch_comb_ofst_bandedge_nonzero_bw20, [15:8] r_ch_comb_ofst_bandedge_nonzero_bw160, [7:0] r_ch_comb_common_diff_db
0xD934 REG_AX_PWR_TSSI_TABLE11
  [31:24] r_ch_comb_ofst_bandedge_zero_bw40, [23:16] r_ch_comb_ofst_bandedge_zero_bw20, [15:8] r_ch_comb_ofst_bandedge_zero_bw160, [7:0] r_ch_comb_ofst_bandedge_nonzero_bw80
0xD938 REG_AX_PWR_TSSI_TABLE12
  [31:24] r_f_pwr_ofst_out_seg0_db, [23:16] r_f_ch20_with_data_nonlegacy_val, [15:8] r_f_ch20_with_data_legacy_val, [7:0] r_ch_comb_ofst_bandedge_zero_bw80
0xD93C REG_AX_PWR_TSSI_TABLE13
  [31:24] r_hemu_init_diff_seg0_db, [23:16] r_heer_init_ofst_seg0_db, [15:8] r_heer_init_diff_seg0_db, [7:0] r_f_tssi_diff_out_seg0_db
0xD940 REG_AX_PWR_TSSI_TABLE14
  [31:24] r_hetb_init_diff_athestf_seg0_db, [23:16] r_hesu_init_ofst_seg0_db, [15:8] r_hesu_init_diff_seg0_db, [7:0] r_hemu_init_ofst_seg0_db
0xD944 REG_AX_PWR_TSSI_TABLE15
  [31:24] r_ht_init_diff_seg0_db, [23:16] r_hetb_init_ofst_seg0_db, [15:8] r_hetb_init_ofst_athestf_seg0_db, [7:0] r_hetb_init_diff_seg0_db
0xD948 REG_AX_PWR_TSSI_TABLE16
  [31:24] r_vht_init_diff_seg0_db, [23:16] r_legacy_init_ofst_seg0_db, [15:8] r_legacy_init_diff_seg0_db, [7:0] r_ht_init_ofst_seg0_db
0xD94C REG_AX_PWR_TSSI_TABLE17
  [31:30] r_bandedge_cfg, [29:26] r_f_rate_idx, [25:22] r_f_format, [21:18] r_bandedge_nonlegacy_rateidx_th, [17:14] r_bandedge_legacy_rateidx_th, [13:8] r_tssi_ctrl_mac_dbg_sel, [7:0] r_vht_init_ofst_seg0_db
0xD950 REG_AX_PWR_TSSI_TABLE18
  [31] r_f_heer_bypass_cbw_fltr_en, [30] r_f_heer_bandedge_ind_val, [29] r_f_heer_bandedge_ind_en, [28] r_f_format_en, [27] r_f_fast_mode_comp_init_en, [26] r_f_dbw_en, [25] r_f_ch20_with_data_en, [24] r_f_cbw_en, [23] r_f_bmode_ofst_out_en, [22] r_f_bmode_diff_out_en, [21] r_f_bmode_bypass_dbw_fltr_en, [20] r_f_bmode_bypass_cbw_fltr_en, [19] r_f_bmode_bandedge_ind_val, [18] r_f_bmode_bandedge_ind_en, [17] r_f_bandedge_cfg_sustbc_en, [16] r_f_bandedge_cfg_sudcm_en, [15] r_f_bandedge_cfg_subf_en, [14] r_f_bandedge_cfg_ndp_en, [13] r_f_bandedge_cfg_mu_en, [12] r_f_bandedge_cfg_hetb_en, [11] r_ch20_with_data_nonlegacy_swap, [10] r_ch20_with_data_legacy_swap, [9:8] r_f_precoding_mode_idx, [7:6] r_f_dbw, [5:4] r_f_cbw, [3:0] r_f_txsc
0xD954 REG_AX_PWR_TSSI_TABLE19
  [31] r_f_is_su_stbc, [30] r_f_is_su_dcm_en, [29] r_f_is_su_dcm, [28] r_f_is_ndp_en, [27] r_f_is_ndp, [26] r_f_ht_ofst_out_en, [25] r_f_ht_diff_out_en, [24] r_f_ht_bypass_dbw_fltr_en, [23] r_f_ht_bypass_cbw_fltr_en, [22] r_f_ht_bandedge_ind_val, [21] r_f_ht_bandedge_ind_en, [20] r_f_hetb_ofst_out_en, [19] r_f_hetb_diff_out_en, [18] r_f_hetb_bypass_dbw_fltr_en, [17] r_f_hetb_bypass_cbw_fltr_en, [16] r_f_hetb_bandedge_ind_val, [15] r_f_hetb_bandedge_ind_en, [14] r_f_hesu_ofst_out_en, [13] r_f_hesu_diff_out_en, [12] r_f_hesu_bypass_dbw_fltr_en, [11] r_f_hesu_bypass_cbw_fltr_en, [10] r_f_hesu_bandedge_ind_val, [9] r_f_hesu_bandedge_ind_en, [8] r_f_hemu_ofst_out_en, [7] r_f_hemu_diff_out_en, [6] r_f_hemu_bypass_dbw_fltr_en, [5] r_f_hemu_bypass_cbw_fltr_en, [4] r_f_hemu_bandedge_ind_val, [3] r_f_hemu_bandedge_ind_en, [2] r_f_heer_ofst_out_en, [1] r_f_heer_diff_out_en, [0] r_f_heer_bypass_dbw_fltr_en
0xD958 REG_AX_PWR_TSSI_TABLE20
  [22] r_tssi_ctrl_mac_use_normal_rate_idx_only, [21] r_tssi_ctrl_mac_dbg_dis, [20] r_tssi_ctrl_mac_clr, [19] r_hetb_pwr_msr_mode, [18] r_f_vht_ofst_out_en, [17] r_f_vht_diff_out_en, [16] r_f_vht_bypass_dbw_fltr_en, [15] r_f_vht_bypass_cbw_fltr_en, [14] r_f_vht_bandedge_ind_val, [13] r_f_vht_bandedge_ind_en, [12] r_f_txsc_en, [11] r_f_tssi_ctrl_out_en, [10] r_f_tssi_ctrl_fast_mode_idx_en, [9] r_f_tssi_ctrl_fast_mode_idx, [8] r_f_rate_idx_en, [7] r_f_precoding_mode_idx_en, [6] r_f_legacy_ofst_out_en, [5] r_f_legacy_diff_out_en, [4] r_f_legacy_bypass_dbw_fltr_en, [3] r_f_legacy_bypass_cbw_fltr_en, [2] r_f_legacy_bandedge_ind_val, [1] r_f_legacy_bandedge_ind_en, [0] r_f_is_su_stbc_en

## Notices in the file
Copyright (C) 2012-2025 Realsil Limited. All rights reserved.
